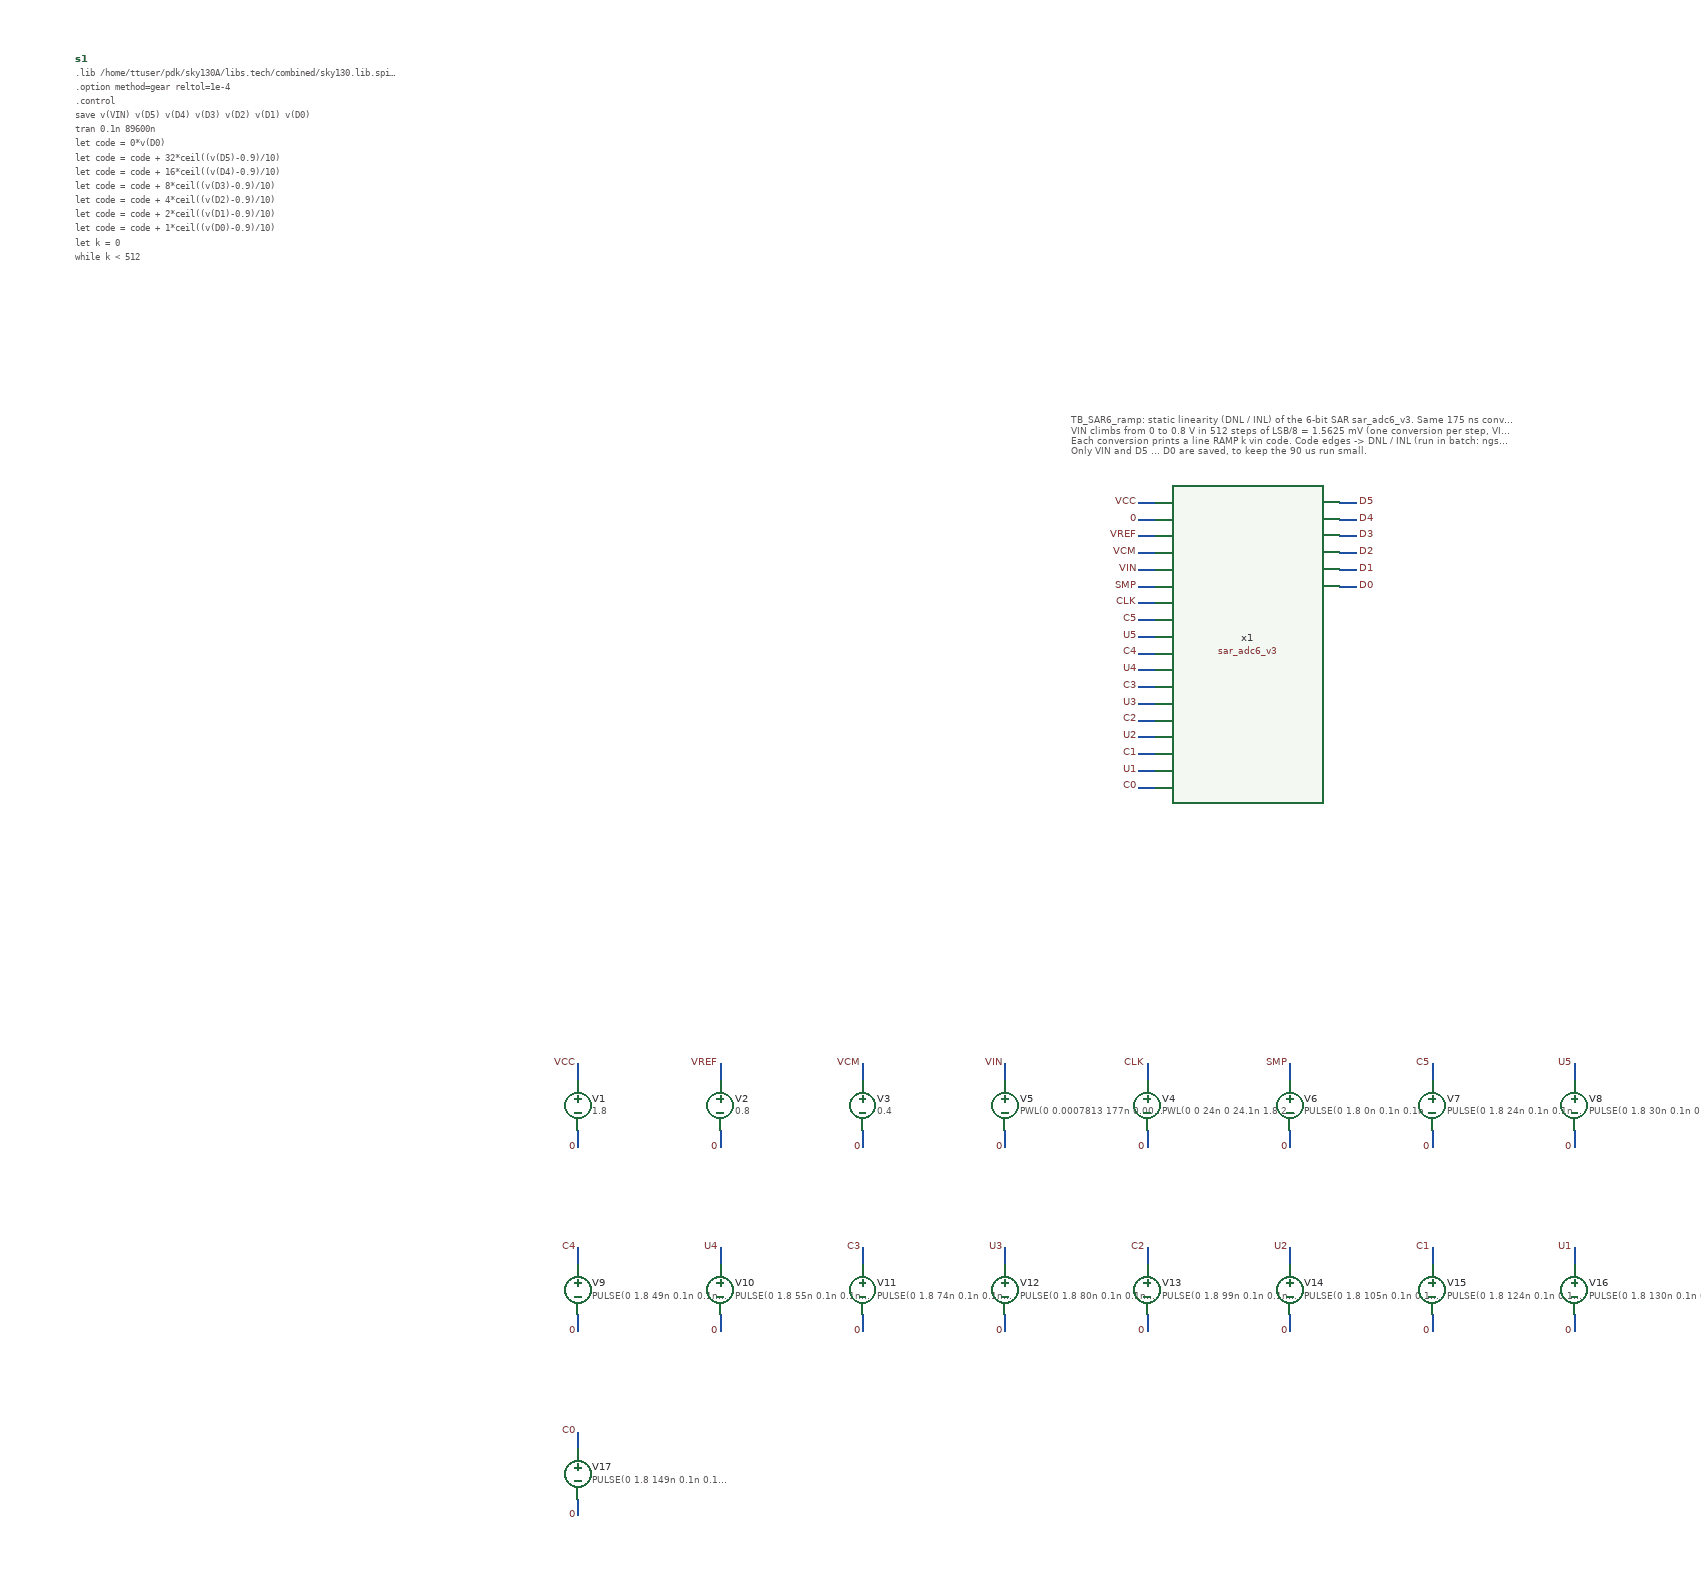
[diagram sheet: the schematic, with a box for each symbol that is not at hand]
v {xschem version=3.4.5 file_version=1.2
}
G {}
K {}
V {}
S {}
E {}
T {TB_SAR6_ramp: static linearity (DNL / INL) of the 6-bit SAR sar_adc6_v3.  Same 175 ns conversion timing as TB_SAR6_v3.
VIN climbs from 0 to 0.8 V in 512 steps of LSB/8 = 1.5625 mV (one conversion per step, VIN changes 2 ns into SMP).
Each conversion prints a line  RAMP k vin code.  Code edges -> DNL / INL (run in batch:  ngspice -b TB_SAR6_ramp.spice > ramp_log.txt).
Only VIN and D5 ... D0 are saved, to keep the 90 us run small.} 290 -630 0 0 0.3 0.3 {}
C {/home/ttuser/Documents/ADCAnalogDesign/SAR_improved/sar_adc6_v3.sym} 500 -350 0 0 {name=x1}
N 390 -520 370 -520 {}
C {lab_pin.sym} 370 -520 0 0 {name=l1 sig_type=std_logic lab=VCC}
N 390 -500 370 -500 {}
C {lab_pin.sym} 370 -500 0 0 {name=l2 sig_type=std_logic lab=0}
N 390 -480 370 -480 {}
C {lab_pin.sym} 370 -480 0 0 {name=l3 sig_type=std_logic lab=VREF}
N 390 -460 370 -460 {}
C {lab_pin.sym} 370 -460 0 0 {name=l4 sig_type=std_logic lab=VCM}
N 390 -440 370 -440 {}
C {lab_pin.sym} 370 -440 0 0 {name=l5 sig_type=std_logic lab=VIN}
N 390 -420 370 -420 {}
C {lab_pin.sym} 370 -420 0 0 {name=l6 sig_type=std_logic lab=SMP}
N 390 -400 370 -400 {}
C {lab_pin.sym} 370 -400 0 0 {name=l7 sig_type=std_logic lab=CLK}
N 390 -380 370 -380 {}
C {lab_pin.sym} 370 -380 0 0 {name=l8 sig_type=std_logic lab=C5}
N 390 -360 370 -360 {}
C {lab_pin.sym} 370 -360 0 0 {name=l9 sig_type=std_logic lab=U5}
N 390 -340 370 -340 {}
C {lab_pin.sym} 370 -340 0 0 {name=l10 sig_type=std_logic lab=C4}
N 390 -320 370 -320 {}
C {lab_pin.sym} 370 -320 0 0 {name=l11 sig_type=std_logic lab=U4}
N 390 -300 370 -300 {}
C {lab_pin.sym} 370 -300 0 0 {name=l12 sig_type=std_logic lab=C3}
N 390 -280 370 -280 {}
C {lab_pin.sym} 370 -280 0 0 {name=l13 sig_type=std_logic lab=U3}
N 390 -260 370 -260 {}
C {lab_pin.sym} 370 -260 0 0 {name=l14 sig_type=std_logic lab=C2}
N 390 -240 370 -240 {}
C {lab_pin.sym} 370 -240 0 0 {name=l15 sig_type=std_logic lab=U2}
N 390 -220 370 -220 {}
C {lab_pin.sym} 370 -220 0 0 {name=l16 sig_type=std_logic lab=C1}
N 390 -200 370 -200 {}
C {lab_pin.sym} 370 -200 0 0 {name=l17 sig_type=std_logic lab=U1}
N 390 -180 370 -180 {}
C {lab_pin.sym} 370 -180 0 0 {name=l18 sig_type=std_logic lab=C0}
N 610 -520 630 -520 {}
C {lab_pin.sym} 630 -520 0 1 {name=l19 sig_type=std_logic lab=D5}
N 610 -500 630 -500 {}
C {lab_pin.sym} 630 -500 0 1 {name=l20 sig_type=std_logic lab=D4}
N 610 -480 630 -480 {}
C {lab_pin.sym} 630 -480 0 1 {name=l21 sig_type=std_logic lab=D3}
N 610 -460 630 -460 {}
C {lab_pin.sym} 630 -460 0 1 {name=l22 sig_type=std_logic lab=D2}
N 610 -440 630 -440 {}
C {lab_pin.sym} 630 -440 0 1 {name=l23 sig_type=std_logic lab=D1}
N 610 -420 630 -420 {}
C {lab_pin.sym} 630 -420 0 1 {name=l24 sig_type=std_logic lab=D0}
C {vsource.sym} -300 200 0 0 {name=V1 value="1.8" savecurrent=false}
N -300 170 -300 150 {}
C {lab_pin.sym} -300 150 0 0 {name=l25 sig_type=std_logic lab=VCC}
N -300 230 -300 250 {}
C {lab_pin.sym} -300 250 0 0 {name=l26 sig_type=std_logic lab=0}
C {vsource.sym} -130 200 0 0 {name=V2 value="0.8" savecurrent=false}
N -130 170 -130 150 {}
C {lab_pin.sym} -130 150 0 0 {name=l27 sig_type=std_logic lab=VREF}
N -130 230 -130 250 {}
C {lab_pin.sym} -130 250 0 0 {name=l28 sig_type=std_logic lab=0}
C {vsource.sym} 40 200 0 0 {name=V3 value="0.4" savecurrent=false}
N 40 170 40 150 {}
C {lab_pin.sym} 40 150 0 0 {name=l29 sig_type=std_logic lab=VCM}
N 40 230 40 250 {}
C {lab_pin.sym} 40 250 0 0 {name=l30 sig_type=std_logic lab=0}
C {vsource.sym} 210 200 0 0 {name=V5 value="PWL(0 0.0007813 177n 0.0007813 177.5n 0.0023438 352n 0.0023438 352.5n 0.0039062 527n 0.0039062 527.5n 0.0054688 702n 0.0054688 702.5n 0.0070313 877n 0.0070313 877.5n 0.0085938 1052n 0.0085938 1052.5n 0.0101563 1227n 0.0101563 1227.5n 0.0117188 1402n 0.0117188 1402.5n 0.0132813 1577n 0.0132813 1577.5n 0.0148438 1752n 0.0148438 1752.5n 0.0164063 1927n 0.0164063 1927.5n 0.0179688 2102n 0.0179688 2102.5n 0.0195312 2277n 0.0195312 2277.5n 0.0210938 2452n 0.0210938 2452.5n 0.0226563 2627n 0.0226563 2627.5n 0.0242188 2802n 0.0242188 2802.5n 0.0257813 2977n 0.0257813 2977.5n 0.0273438 3152n 0.0273438 3152.5n 0.0289063 3327n 0.0289063 3327.5n 0.0304688 3502n 0.0304688 3502.5n 0.0320313 3677n 0.0320313 3677.5n 0.0335937 3852n 0.0335937 3852.5n 0.0351562 4027n 0.0351562 4027.5n 0.0367188 4202n 0.0367188 4202.5n 0.0382813 4377n 0.0382813 4377.5n 0.0398438 4552n 0.0398438 4552.5n 0.0414063 4727n 0.0414063 4727.5n 0.0429688 4902n 0.0429688 4902.5n 0.0445313 5077n 0.0445313 5077.5n 0.0460938 5252n 0.0460938 5252.5n 0.0476563 5427n 0.0476563 5427.5n 0.0492188 5602n 0.0492188 5602.5n 0.0507812 5777n 0.0507812 5777.5n 0.0523438 5952n 0.0523438 5952.5n 0.0539063 6127n 0.0539063 6127.5n 0.0554688 6302n 0.0554688 6302.5n 0.0570313 6477n 0.0570313 6477.5n 0.0585938 6652n 0.0585938 6652.5n 0.0601563 6827n 0.0601563 6827.5n 0.0617188 7002n 0.0617188 7002.5n 0.0632812 7177n 0.0632812 7177.5n 0.0648438 7352n 0.0648438 7352.5n 0.0664062 7527n 0.0664062 7527.5n 0.0679688 7702n 0.0679688 7702.5n 0.0695313 7877n 0.0695313 7877.5n 0.0710937 8052n 0.0710937 8052.5n 0.0726563 8227n 0.0726563 8227.5n 0.0742188 8402n 0.0742188 8402.5n 0.0757813 8577n 0.0757813 8577.5n 0.0773438 8752n 0.0773438 8752.5n 0.0789063 8927n 0.0789063 8927.5n 0.0804688 9102n 0.0804688 9102.5n 0.0820312 9277n 0.0820312 9277.5n 0.0835938 9452n 0.0835938 9452.5n 0.0851563 9627n 0.0851563 9627.5n 0.0867188 9802n 0.0867188 9802.5n 0.0882813 9977n 0.0882813 9977.5n 0.0898438 10152n 0.0898438 10152.5n 0.0914063 10327n 0.0914063 10327.5n 0.0929688 10502n 0.0929688 10502.5n 0.0945313 10677n 0.0945313 10677.5n 0.0960938 10852n 0.0960938 10852.5n 0.0976562 11027n 0.0976562 11027.5n 0.0992188 11202n 0.0992188 11202.5n 0.1007813 11377n 0.1007813 11377.5n 0.1023438 11552n 0.1023438 11552.5n 0.1039063 11727n 0.1039063 11727.5n 0.1054688 11902n 0.1054688 11902.5n 0.1070313 12077n 0.1070313 12077.5n 0.1085938 12252n 0.1085938 12252.5n 0.1101563 12427n 0.1101563 12427.5n 0.1117188 12602n 0.1117188 12602.5n 0.1132812 12777n 0.1132812 12777.5n 0.1148438 12952n 0.1148438 12952.5n 0.1164063 13127n 0.1164063 13127.5n 0.1179688 13302n 0.1179688 13302.5n 0.1195313 13477n 0.1195313 13477.5n 0.1210938 13652n 0.1210938 13652.5n 0.1226563 13827n 0.1226563 13827.5n 0.1242188 14002n 0.1242188 14002.5n 0.1257813 14177n 0.1257813 14177.5n 0.1273438 14352n 0.1273438 14352.5n 0.1289062 14527n 0.1289062 14527.5n 0.1304687 14702n 0.1304687 14702.5n 0.1320313 14877n 0.1320313 14877.5n 0.1335938 15052n 0.1335938 15052.5n 0.1351563 15227n 0.1351563 15227.5n 0.1367188 15402n 0.1367188 15402.5n 0.1382812 15577n 0.1382812 15577.5n 0.1398438 15752n 0.1398438 15752.5n 0.1414063 15927n 0.1414063 15927.5n 0.1429688 16102n 0.1429688 16102.5n 0.1445312 16277n 0.1445312 16277.5n 0.1460937 16452n 0.1460937 16452.5n 0.1476563 16627n 0.1476563 16627.5n 0.1492188 16802n 0.1492188 16802.5n 0.1507813 16977n 0.1507813 16977.5n 0.1523438 17152n 0.1523438 17152.5n 0.1539063 17327n 0.1539063 17327.5n 0.1554688 17502n 0.1554688 17502.5n 0.1570313 17677n 0.1570313 17677.5n 0.1585938 17852n 0.1585938 17852.5n 0.1601562 18027n 0.1601562 18027.5n 0.1617188 18202n 0.1617188 18202.5n 0.1632813 18377n 0.1632813 18377.5n 0.1648438 18552n 0.1648438 18552.5n 0.1664063 18727n 0.1664063 18727.5n 0.1679688 18902n 0.1679688 18902.5n 0.1695313 19077n 0.1695313 19077.5n 0.1710938 19252n 0.1710938 19252.5n 0.1726563 19427n 0.1726563 19427.5n 0.1742188 19602n 0.1742188 19602.5n 0.1757812 19777n 0.1757812 19777.5n 0.1773438 19952n 0.1773438 19952.5n 0.1789063 20127n 0.1789063 20127.5n 0.1804688 20302n 0.1804688 20302.5n 0.1820313 20477n 0.1820313 20477.5n 0.1835938 20652n 0.1835938 20652.5n 0.1851563 20827n 0.1851563 20827.5n 0.1867188 21002n 0.1867188 21002.5n 0.1882813 21177n 0.1882813 21177.5n 0.1898438 21352n 0.1898438 21352.5n 0.1914062 21527n 0.1914062 21527.5n 0.1929688 21702n 0.1929688 21702.5n 0.1945313 21877n 0.1945313 21877.5n 0.1960938 22052n 0.1960938 22052.5n 0.1976563 22227n 0.1976563 22227.5n 0.1992188 22402n 0.1992188 22402.5n 0.2007813 22577n 0.2007813 22577.5n 0.2023438 22752n 0.2023438 22752.5n 0.2039063 22927n 0.2039063 22927.5n 0.2054688 23102n 0.2054688 23102.5n 0.2070312 23277n 0.2070312 23277.5n 0.2085938 23452n 0.2085938 23452.5n 0.2101563 23627n 0.2101563 23627.5n 0.2117188 23802n 0.2117188 23802.5n 0.2132813 23977n 0.2132813 23977.5n 0.2148438 24152n 0.2148438 24152.5n 0.2164063 24327n 0.2164063 24327.5n 0.2179688 24502n 0.2179688 24502.5n 0.2195313 24677n 0.2195313 24677.5n 0.2210938 24852n 0.2210938 24852.5n 0.2226562 25027n 0.2226562 25027.5n 0.2242188 25202n 0.2242188 25202.5n 0.2257813 25377n 0.2257813 25377.5n 0.2273438 25552n 0.2273438 25552.5n 0.2289063 25727n 0.2289063 25727.5n 0.2304688 25902n 0.2304688 25902.5n 0.2320313 26077n 0.2320313 26077.5n 0.2335938 26252n 0.2335938 26252.5n 0.2351563 26427n 0.2351563 26427.5n 0.2367188 26602n 0.2367188 26602.5n 0.2382812 26777n 0.2382812 26777.5n 0.2398438 26952n 0.2398438 26952.5n 0.2414063 27127n 0.2414063 27127.5n 0.2429688 27302n 0.2429688 27302.5n 0.2445313 27477n 0.2445313 27477.5n 0.2460938 27652n 0.2460938 27652.5n 0.2476563 27827n 0.2476563 27827.5n 0.2492188 28002n 0.2492188 28002.5n 0.2507813 28177n 0.2507813 28177.5n 0.2523438 28352n 0.2523438 28352.5n 0.2539062 28527n 0.2539062 28527.5n 0.2554688 28702n 0.2554688 28702.5n 0.2570312 28877n 0.2570312 28877.5n 0.2585938 29052n 0.2585938 29052.5n 0.2601563 29227n 0.2601563 29227.5n 0.2617188 29402n 0.2617188 29402.5n 0.2632813 29577n 0.2632813 29577.5n 0.2648437 29752n 0.2648437 29752.5n 0.2664063 29927n 0.2664063 29927.5n 0.2679688 30102n 0.2679688 30102.5n 0.2695312 30277n 0.2695312 30277.5n 0.2710938 30452n 0.2710938 30452.5n 0.2726562 30627n 0.2726562 30627.5n 0.2742188 30802n 0.2742188 30802.5n 0.2757813 30977n 0.2757813 30977.5n 0.2773438 31152n 0.2773438 31152.5n 0.2789063 31327n 0.2789063 31327.5n 0.2804687 31502n 0.2804687 31502.5n 0.2820313 31677n 0.2820313 31677.5n 0.2835938 31852n 0.2835938 31852.5n 0.2851562 32027n 0.2851562 32027.5n 0.2867188 32202n 0.2867188 32202.5n 0.2882812 32377n 0.2882812 32377.5n 0.2898438 32552n 0.2898438 32552.5n 0.2914063 32727n 0.2914063 32727.5n 0.2929688 32902n 0.2929688 32902.5n 0.2945313 33077n 0.2945313 33077.5n 0.2960937 33252n 0.2960937 33252.5n 0.2976563 33427n 0.2976563 33427.5n 0.2992188 33602n 0.2992188 33602.5n 0.3007812 33777n 0.3007812 33777.5n 0.3023438 33952n 0.3023438 33952.5n 0.3039063 34127n 0.3039063 34127.5n 0.3054688 34302n 0.3054688 34302.5n 0.3070313 34477n 0.3070313 34477.5n 0.3085938 34652n 0.3085938 34652.5n 0.3101563 34827n 0.3101563 34827.5n 0.3117188 35002n 0.3117188 35002.5n 0.3132813 35177n 0.3132813 35177.5n 0.3148438 35352n 0.3148438 35352.5n 0.3164062 35527n 0.3164062 35527.5n 0.3179688 35702n 0.3179688 35702.5n 0.3195313 35877n 0.3195313 35877.5n 0.3210938 36052n 0.3210938 36052.5n 0.3226563 36227n 0.3226563 36227.5n 0.3242188 36402n 0.3242188 36402.5n 0.3257813 36577n 0.3257813 36577.5n 0.3273438 36752n 0.3273438 36752.5n 0.3289063 36927n 0.3289063 36927.5n 0.3304688 37102n 0.3304688 37102.5n 0.3320312 37277n 0.3320312 37277.5n 0.3335938 37452n 0.3335938 37452.5n 0.3351563 37627n 0.3351563 37627.5n 0.3367188 37802n 0.3367188 37802.5n 0.3382813 37977n 0.3382813 37977.5n 0.3398438 38152n 0.3398438 38152.5n 0.3414063 38327n 0.3414063 38327.5n 0.3429688 38502n 0.3429688 38502.5n 0.3445313 38677n 0.3445313 38677.5n 0.3460938 38852n 0.3460938 38852.5n 0.3476562 39027n 0.3476562 39027.5n 0.3492188 39202n 0.3492188 39202.5n 0.3507813 39377n 0.3507813 39377.5n 0.3523438 39552n 0.3523438 39552.5n 0.3539063 39727n 0.3539063 39727.5n 0.3554688 39902n 0.3554688 39902.5n 0.3570313 40077n 0.3570313 40077.5n 0.3585938 40252n 0.3585938 40252.5n 0.3601563 40427n 0.3601563 40427.5n 0.3617188 40602n 0.3617188 40602.5n 0.3632812 40777n 0.3632812 40777.5n 0.3648438 40952n 0.3648438 40952.5n 0.3664063 41127n 0.3664063 41127.5n 0.3679688 41302n 0.3679688 41302.5n 0.3695313 41477n 0.3695313 41477.5n 0.3710938 41652n 0.3710938 41652.5n 0.3726563 41827n 0.3726563 41827.5n 0.3742188 42002n 0.3742188 42002.5n 0.3757813 42177n 0.3757813 42177.5n 0.3773438 42352n 0.3773438 42352.5n 0.3789062 42527n 0.3789062 42527.5n 0.3804688 42702n 0.3804688 42702.5n 0.3820313 42877n 0.3820313 42877.5n 0.3835938 43052n 0.3835938 43052.5n 0.3851563 43227n 0.3851563 43227.5n 0.3867188 43402n 0.3867188 43402.5n 0.3882813 43577n 0.3882813 43577.5n 0.3898438 43752n 0.3898438 43752.5n 0.3914063 43927n 0.3914063 43927.5n 0.3929688 44102n 0.3929688 44102.5n 0.3945312 44277n 0.3945312 44277.5n 0.3960938 44452n 0.3960938 44452.5n 0.3976563 44627n 0.3976563 44627.5n 0.3992188 44802n 0.3992188 44802.5n 0.4007813 44977n 0.4007813 44977.5n 0.4023438 45152n 0.4023438 45152.5n 0.4039063 45327n 0.4039063 45327.5n 0.4054688 45502n 0.4054688 45502.5n 0.4070313 45677n 0.4070313 45677.5n 0.4085938 45852n 0.4085938 45852.5n 0.4101562 46027n 0.4101562 46027.5n 0.4117188 46202n 0.4117188 46202.5n 0.4132813 46377n 0.4132813 46377.5n 0.4148438 46552n 0.4148438 46552.5n 0.4164063 46727n 0.4164063 46727.5n 0.4179688 46902n 0.4179688 46902.5n 0.4195313 47077n 0.4195313 47077.5n 0.4210938 47252n 0.4210938 47252.5n 0.4226563 47427n 0.4226563 47427.5n 0.4242188 47602n 0.4242188 47602.5n 0.4257812 47777n 0.4257812 47777.5n 0.4273438 47952n 0.4273438 47952.5n 0.4289063 48127n 0.4289063 48127.5n 0.4304688 48302n 0.4304688 48302.5n 0.4320313 48477n 0.4320313 48477.5n 0.4335938 48652n 0.4335938 48652.5n 0.4351563 48827n 0.4351563 48827.5n 0.4367188 49002n 0.4367188 49002.5n 0.4382813 49177n 0.4382813 49177.5n 0.4398438 49352n 0.4398438 49352.5n 0.4414062 49527n 0.4414062 49527.5n 0.4429688 49702n 0.4429688 49702.5n 0.4445313 49877n 0.4445313 49877.5n 0.4460938 50052n 0.4460938 50052.5n 0.4476563 50227n 0.4476563 50227.5n 0.4492188 50402n 0.4492188 50402.5n 0.4507813 50577n 0.4507813 50577.5n 0.4523438 50752n 0.4523438 50752.5n 0.4539063 50927n 0.4539063 50927.5n 0.4554688 51102n 0.4554688 51102.5n 0.4570312 51277n 0.4570312 51277.5n 0.4585938 51452n 0.4585938 51452.5n 0.4601563 51627n 0.4601563 51627.5n 0.4617188 51802n 0.4617188 51802.5n 0.4632813 51977n 0.4632813 51977.5n 0.4648438 52152n 0.4648438 52152.5n 0.4664063 52327n 0.4664063 52327.5n 0.4679688 52502n 0.4679688 52502.5n 0.4695313 52677n 0.4695313 52677.5n 0.4710938 52852n 0.4710938 52852.5n 0.4726562 53027n 0.4726562 53027.5n 0.4742188 53202n 0.4742188 53202.5n 0.4757813 53377n 0.4757813 53377.5n 0.4773438 53552n 0.4773438 53552.5n 0.4789063 53727n 0.4789063 53727.5n 0.4804688 53902n 0.4804688 53902.5n 0.4820313 54077n 0.4820313 54077.5n 0.4835938 54252n 0.4835938 54252.5n 0.4851563 54427n 0.4851563 54427.5n 0.4867188 54602n 0.4867188 54602.5n 0.4882812 54777n 0.4882812 54777.5n 0.4898438 54952n 0.4898438 54952.5n 0.4914063 55127n 0.4914063 55127.5n 0.4929688 55302n 0.4929688 55302.5n 0.4945313 55477n 0.4945313 55477.5n 0.4960938 55652n 0.4960938 55652.5n 0.4976563 55827n 0.4976563 55827.5n 0.4992188 56002n 0.4992188 56002.5n 0.5007813 56177n 0.5007813 56177.5n 0.5023437 56352n 0.5023437 56352.5n 0.5039062 56527n 0.5039062 56527.5n 0.5054688 56702n 0.5054688 56702.5n 0.5070313 56877n 0.5070313 56877.5n 0.5085938 57052n 0.5085938 57052.5n 0.5101562 57227n 0.5101562 57227.5n 0.5117188 57402n 0.5117188 57402.5n 0.5132813 57577n 0.5132813 57577.5n 0.5148438 57752n 0.5148438 57752.5n 0.5164063 57927n 0.5164063 57927.5n 0.5179687 58102n 0.5179687 58102.5n 0.5195312 58277n 0.5195312 58277.5n 0.5210938 58452n 0.5210938 58452.5n 0.5226563 58627n 0.5226563 58627.5n 0.5242188 58802n 0.5242188 58802.5n 0.5257812 58977n 0.5257812 58977.5n 0.5273438 59152n 0.5273438 59152.5n 0.5289063 59327n 0.5289063 59327.5n 0.5304688 59502n 0.5304688 59502.5n 0.5320313 59677n 0.5320313 59677.5n 0.5335937 59852n 0.5335937 59852.5n 0.5351562 60027n 0.5351562 60027.5n 0.5367188 60202n 0.5367188 60202.5n 0.5382813 60377n 0.5382813 60377.5n 0.5398438 60552n 0.5398438 60552.5n 0.5414062 60727n 0.5414062 60727.5n 0.5429688 60902n 0.5429688 60902.5n 0.5445313 61077n 0.5445313 61077.5n 0.5460938 61252n 0.5460938 61252.5n 0.5476563 61427n 0.5476563 61427.5n 0.5492187 61602n 0.5492187 61602.5n 0.5507812 61777n 0.5507812 61777.5n 0.5523438 61952n 0.5523438 61952.5n 0.5539063 62127n 0.5539063 62127.5n 0.5554688 62302n 0.5554688 62302.5n 0.5570312 62477n 0.5570312 62477.5n 0.5585938 62652n 0.5585938 62652.5n 0.5601563 62827n 0.5601563 62827.5n 0.5617188 63002n 0.5617188 63002.5n 0.5632813 63177n 0.5632813 63177.5n 0.5648437 63352n 0.5648437 63352.5n 0.5664062 63527n 0.5664062 63527.5n 0.5679688 63702n 0.5679688 63702.5n 0.5695313 63877n 0.5695313 63877.5n 0.5710938 64052n 0.5710938 64052.5n 0.5726562 64227n 0.5726562 64227.5n 0.5742188 64402n 0.5742188 64402.5n 0.5757813 64577n 0.5757813 64577.5n 0.5773438 64752n 0.5773438 64752.5n 0.5789063 64927n 0.5789063 64927.5n 0.5804687 65102n 0.5804687 65102.5n 0.5820312 65277n 0.5820312 65277.5n 0.5835938 65452n 0.5835938 65452.5n 0.5851563 65627n 0.5851563 65627.5n 0.5867188 65802n 0.5867188 65802.5n 0.5882812 65977n 0.5882812 65977.5n 0.5898438 66152n 0.5898438 66152.5n 0.5914063 66327n 0.5914063 66327.5n 0.5929688 66502n 0.5929688 66502.5n 0.5945313 66677n 0.5945313 66677.5n 0.5960937 66852n 0.5960937 66852.5n 0.5976562 67027n 0.5976562 67027.5n 0.5992188 67202n 0.5992188 67202.5n 0.6007813 67377n 0.6007813 67377.5n 0.6023438 67552n 0.6023438 67552.5n 0.6039063 67727n 0.6039063 67727.5n 0.6054688 67902n 0.6054688 67902.5n 0.6070313 68077n 0.6070313 68077.5n 0.6085938 68252n 0.6085938 68252.5n 0.6101563 68427n 0.6101563 68427.5n 0.6117188 68602n 0.6117188 68602.5n 0.6132812 68777n 0.6132812 68777.5n 0.6148438 68952n 0.6148438 68952.5n 0.6164063 69127n 0.6164063 69127.5n 0.6179688 69302n 0.6179688 69302.5n 0.6195313 69477n 0.6195313 69477.5n 0.6210938 69652n 0.6210938 69652.5n 0.6226563 69827n 0.6226563 69827.5n 0.6242188 70002n 0.6242188 70002.5n 0.6257813 70177n 0.6257813 70177.5n 0.6273438 70352n 0.6273438 70352.5n 0.6289062 70527n 0.6289062 70527.5n 0.6304688 70702n 0.6304688 70702.5n 0.6320313 70877n 0.6320313 70877.5n 0.6335938 71052n 0.6335938 71052.5n 0.6351563 71227n 0.6351563 71227.5n 0.6367188 71402n 0.6367188 71402.5n 0.6382813 71577n 0.6382813 71577.5n 0.6398438 71752n 0.6398438 71752.5n 0.6414063 71927n 0.6414063 71927.5n 0.6429688 72102n 0.6429688 72102.5n 0.6445312 72277n 0.6445312 72277.5n 0.6460938 72452n 0.6460938 72452.5n 0.6476563 72627n 0.6476563 72627.5n 0.6492188 72802n 0.6492188 72802.5n 0.6507813 72977n 0.6507813 72977.5n 0.6523438 73152n 0.6523438 73152.5n 0.6539063 73327n 0.6539063 73327.5n 0.6554688 73502n 0.6554688 73502.5n 0.6570313 73677n 0.6570313 73677.5n 0.6585938 73852n 0.6585938 73852.5n 0.6601562 74027n 0.6601562 74027.5n 0.6617188 74202n 0.6617188 74202.5n 0.6632813 74377n 0.6632813 74377.5n 0.6648438 74552n 0.6648438 74552.5n 0.6664063 74727n 0.6664063 74727.5n 0.6679688 74902n 0.6679688 74902.5n 0.6695313 75077n 0.6695313 75077.5n 0.6710938 75252n 0.6710938 75252.5n 0.6726563 75427n 0.6726563 75427.5n 0.6742188 75602n 0.6742188 75602.5n 0.6757812 75777n 0.6757812 75777.5n 0.6773438 75952n 0.6773438 75952.5n 0.6789063 76127n 0.6789063 76127.5n 0.6804688 76302n 0.6804688 76302.5n 0.6820313 76477n 0.6820313 76477.5n 0.6835938 76652n 0.6835938 76652.5n 0.6851563 76827n 0.6851563 76827.5n 0.6867188 77002n 0.6867188 77002.5n 0.6882813 77177n 0.6882813 77177.5n 0.6898438 77352n 0.6898438 77352.5n 0.6914062 77527n 0.6914062 77527.5n 0.6929688 77702n 0.6929688 77702.5n 0.6945313 77877n 0.6945313 77877.5n 0.6960938 78052n 0.6960938 78052.5n 0.6976563 78227n 0.6976563 78227.5n 0.6992188 78402n 0.6992188 78402.5n 0.7007813 78577n 0.7007813 78577.5n 0.7023438 78752n 0.7023438 78752.5n 0.7039063 78927n 0.7039063 78927.5n 0.7054688 79102n 0.7054688 79102.5n 0.7070312 79277n 0.7070312 79277.5n 0.7085938 79452n 0.7085938 79452.5n 0.7101563 79627n 0.7101563 79627.5n 0.7117188 79802n 0.7117188 79802.5n 0.7132813 79977n 0.7132813 79977.5n 0.7148438 80152n 0.7148438 80152.5n 0.7164063 80327n 0.7164063 80327.5n 0.7179688 80502n 0.7179688 80502.5n 0.7195313 80677n 0.7195313 80677.5n 0.7210938 80852n 0.7210938 80852.5n 0.7226562 81027n 0.7226562 81027.5n 0.7242188 81202n 0.7242188 81202.5n 0.7257813 81377n 0.7257813 81377.5n 0.7273438 81552n 0.7273438 81552.5n 0.7289063 81727n 0.7289063 81727.5n 0.7304688 81902n 0.7304688 81902.5n 0.7320313 82077n 0.7320313 82077.5n 0.7335938 82252n 0.7335938 82252.5n 0.7351563 82427n 0.7351563 82427.5n 0.7367188 82602n 0.7367188 82602.5n 0.7382812 82777n 0.7382812 82777.5n 0.7398438 82952n 0.7398438 82952.5n 0.7414063 83127n 0.7414063 83127.5n 0.7429688 83302n 0.7429688 83302.5n 0.7445313 83477n 0.7445313 83477.5n 0.7460938 83652n 0.7460938 83652.5n 0.7476563 83827n 0.7476563 83827.5n 0.7492188 84002n 0.7492188 84002.5n 0.7507813 84177n 0.7507813 84177.5n 0.7523438 84352n 0.7523438 84352.5n 0.7539062 84527n 0.7539062 84527.5n 0.7554688 84702n 0.7554688 84702.5n 0.7570313 84877n 0.7570313 84877.5n 0.7585938 85052n 0.7585938 85052.5n 0.7601563 85227n 0.7601563 85227.5n 0.7617188 85402n 0.7617188 85402.5n 0.7632813 85577n 0.7632813 85577.5n 0.7648438 85752n 0.7648438 85752.5n 0.7664063 85927n 0.7664063 85927.5n 0.7679688 86102n 0.7679688 86102.5n 0.7695312 86277n 0.7695312 86277.5n 0.7710938 86452n 0.7710938 86452.5n 0.7726563 86627n 0.7726563 86627.5n 0.7742188 86802n 0.7742188 86802.5n 0.7757813 86977n 0.7757813 86977.5n 0.7773438 87152n 0.7773438 87152.5n 0.7789063 87327n 0.7789063 87327.5n 0.7804688 87502n 0.7804688 87502.5n 0.7820313 87677n 0.7820313 87677.5n 0.7835938 87852n 0.7835938 87852.5n 0.7851562 88027n 0.7851562 88027.5n 0.7867188 88202n 0.7867188 88202.5n 0.7882813 88377n 0.7882813 88377.5n 0.7898438 88552n 0.7898438 88552.5n 0.7914063 88727n 0.7914063 88727.5n 0.7929688 88902n 0.7929688 88902.5n 0.7945313 89077n 0.7945313 89077.5n 0.7960938 89252n 0.7960938 89252.5n 0.7976563 89427n 0.7976563 89427.5n 0.7992188)" savecurrent=false}
N 210 170 210 150 {}
C {lab_pin.sym} 210 150 0 0 {name=l31 sig_type=std_logic lab=VIN}
N 210 230 210 250 {}
C {lab_pin.sym} 210 250 0 0 {name=l32 sig_type=std_logic lab=0}
C {vsource.sym} 380 200 0 0 {name=V4 value="PWL(0 0 24n 0 24.1n 1.8 28n 1.8 28.1n 0 49n 0 49.1n 1.8 53n 1.8 53.1n 0 74n 0 74.1n 1.8 78n 1.8 78.1n 0 99n 0 99.1n 1.8 103n 1.8 103.1n 0 124n 0 124.1n 1.8 128n 1.8 128.1n 0 149n 0 149.1n 1.8 153n 1.8 153.1n 0 175n 0) r=0" savecurrent=false}
N 380 170 380 150 {}
C {lab_pin.sym} 380 150 0 0 {name=l33 sig_type=std_logic lab=CLK}
N 380 230 380 250 {}
C {lab_pin.sym} 380 250 0 0 {name=l34 sig_type=std_logic lab=0}
C {vsource.sym} 550 200 0 0 {name=V6 value="PULSE(0 1.8 0n 0.1n 0.1n 19.9n 175n)" savecurrent=false}
N 550 170 550 150 {}
C {lab_pin.sym} 550 150 0 0 {name=l35 sig_type=std_logic lab=SMP}
N 550 230 550 250 {}
C {lab_pin.sym} 550 250 0 0 {name=l36 sig_type=std_logic lab=0}
C {vsource.sym} 720 200 0 0 {name=V7 value="PULSE(0 1.8 24n 0.1n 0.1n 3.9n 175n)" savecurrent=false}
N 720 170 720 150 {}
C {lab_pin.sym} 720 150 0 0 {name=l37 sig_type=std_logic lab=C5}
N 720 230 720 250 {}
C {lab_pin.sym} 720 250 0 0 {name=l38 sig_type=std_logic lab=0}
C {vsource.sym} 890 200 0 0 {name=V8 value="PULSE(0 1.8 30n 0.1n 0.1n 4.9n 175n)" savecurrent=false}
N 890 170 890 150 {}
C {lab_pin.sym} 890 150 0 0 {name=l39 sig_type=std_logic lab=U5}
N 890 230 890 250 {}
C {lab_pin.sym} 890 250 0 0 {name=l40 sig_type=std_logic lab=0}
C {vsource.sym} -300 420 0 0 {name=V9 value="PULSE(0 1.8 49n 0.1n 0.1n 3.9n 175n)" savecurrent=false}
N -300 390 -300 370 {}
C {lab_pin.sym} -300 370 0 0 {name=l41 sig_type=std_logic lab=C4}
N -300 450 -300 470 {}
C {lab_pin.sym} -300 470 0 0 {name=l42 sig_type=std_logic lab=0}
C {vsource.sym} -130 420 0 0 {name=V10 value="PULSE(0 1.8 55n 0.1n 0.1n 4.9n 175n)" savecurrent=false}
N -130 390 -130 370 {}
C {lab_pin.sym} -130 370 0 0 {name=l43 sig_type=std_logic lab=U4}
N -130 450 -130 470 {}
C {lab_pin.sym} -130 470 0 0 {name=l44 sig_type=std_logic lab=0}
C {vsource.sym} 40 420 0 0 {name=V11 value="PULSE(0 1.8 74n 0.1n 0.1n 3.9n 175n)" savecurrent=false}
N 40 390 40 370 {}
C {lab_pin.sym} 40 370 0 0 {name=l45 sig_type=std_logic lab=C3}
N 40 450 40 470 {}
C {lab_pin.sym} 40 470 0 0 {name=l46 sig_type=std_logic lab=0}
C {vsource.sym} 210 420 0 0 {name=V12 value="PULSE(0 1.8 80n 0.1n 0.1n 4.9n 175n)" savecurrent=false}
N 210 390 210 370 {}
C {lab_pin.sym} 210 370 0 0 {name=l47 sig_type=std_logic lab=U3}
N 210 450 210 470 {}
C {lab_pin.sym} 210 470 0 0 {name=l48 sig_type=std_logic lab=0}
C {vsource.sym} 380 420 0 0 {name=V13 value="PULSE(0 1.8 99n 0.1n 0.1n 3.9n 175n)" savecurrent=false}
N 380 390 380 370 {}
C {lab_pin.sym} 380 370 0 0 {name=l49 sig_type=std_logic lab=C2}
N 380 450 380 470 {}
C {lab_pin.sym} 380 470 0 0 {name=l50 sig_type=std_logic lab=0}
C {vsource.sym} 550 420 0 0 {name=V14 value="PULSE(0 1.8 105n 0.1n 0.1n 4.9n 175n)" savecurrent=false}
N 550 390 550 370 {}
C {lab_pin.sym} 550 370 0 0 {name=l51 sig_type=std_logic lab=U2}
N 550 450 550 470 {}
C {lab_pin.sym} 550 470 0 0 {name=l52 sig_type=std_logic lab=0}
C {vsource.sym} 720 420 0 0 {name=V15 value="PULSE(0 1.8 124n 0.1n 0.1n 3.9n 175n)" savecurrent=false}
N 720 390 720 370 {}
C {lab_pin.sym} 720 370 0 0 {name=l53 sig_type=std_logic lab=C1}
N 720 450 720 470 {}
C {lab_pin.sym} 720 470 0 0 {name=l54 sig_type=std_logic lab=0}
C {vsource.sym} 890 420 0 0 {name=V16 value="PULSE(0 1.8 130n 0.1n 0.1n 4.9n 175n)" savecurrent=false}
N 890 390 890 370 {}
C {lab_pin.sym} 890 370 0 0 {name=l55 sig_type=std_logic lab=U1}
N 890 450 890 470 {}
C {lab_pin.sym} 890 470 0 0 {name=l56 sig_type=std_logic lab=0}
C {vsource.sym} -300 640 0 0 {name=V17 value="PULSE(0 1.8 149n 0.1n 0.1n 3.9n 175n)" savecurrent=false}
N -300 610 -300 590 {}
C {lab_pin.sym} -300 590 0 0 {name=l57 sig_type=std_logic lab=C0}
N -300 670 -300 690 {}
C {lab_pin.sym} -300 690 0 0 {name=l58 sig_type=std_logic lab=0}
C {code_shown.sym} -900 -1050 0 0 {name=s1 only_toplevel=false value=".lib /home/ttuser/pdk/sky130A/libs.tech/combined/sky130.lib.spice tt
.option method=gear reltol=1e-4
.control
save v(VIN) v(D5) v(D4) v(D3) v(D2) v(D1) v(D0)
tran 0.1n 89600n
let code = 0*v(D0)
let code = code + 32*ceil((v(D5)-0.9)/10)
let code = code + 16*ceil((v(D4)-0.9)/10)
let code = code + 8*ceil((v(D3)-0.9)/10)
let code = code + 4*ceil((v(D2)-0.9)/10)
let code = code + 2*ceil((v(D1)-0.9)/10)
let code = code + 1*ceil((v(D0)-0.9)/10)
let k = 0
while k < 512
  let tr = k*175e-9 + 165e-9
  meas tran ck find code at=$&tr
  meas tran vk find v(VIN) at=$&tr
  echo RAMP $&k $&vk $&ck
  let k = k + 1
end
plot code
.endc"}
